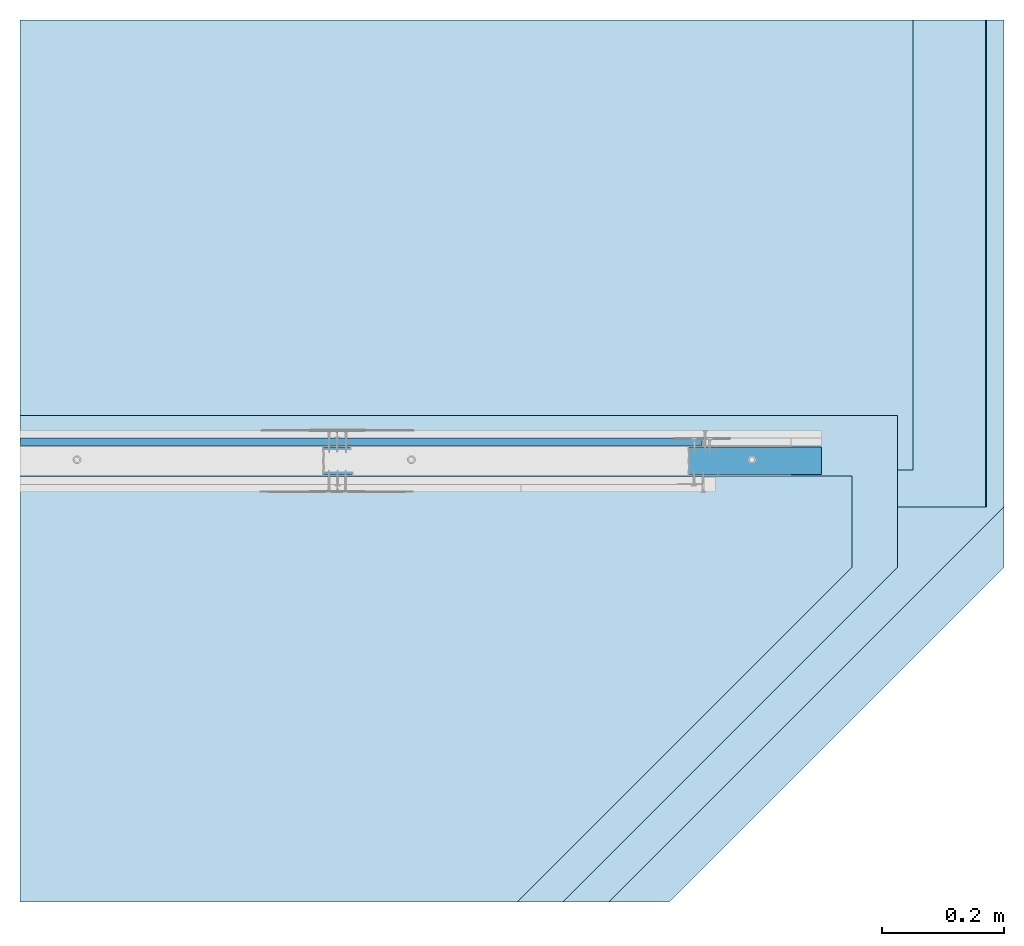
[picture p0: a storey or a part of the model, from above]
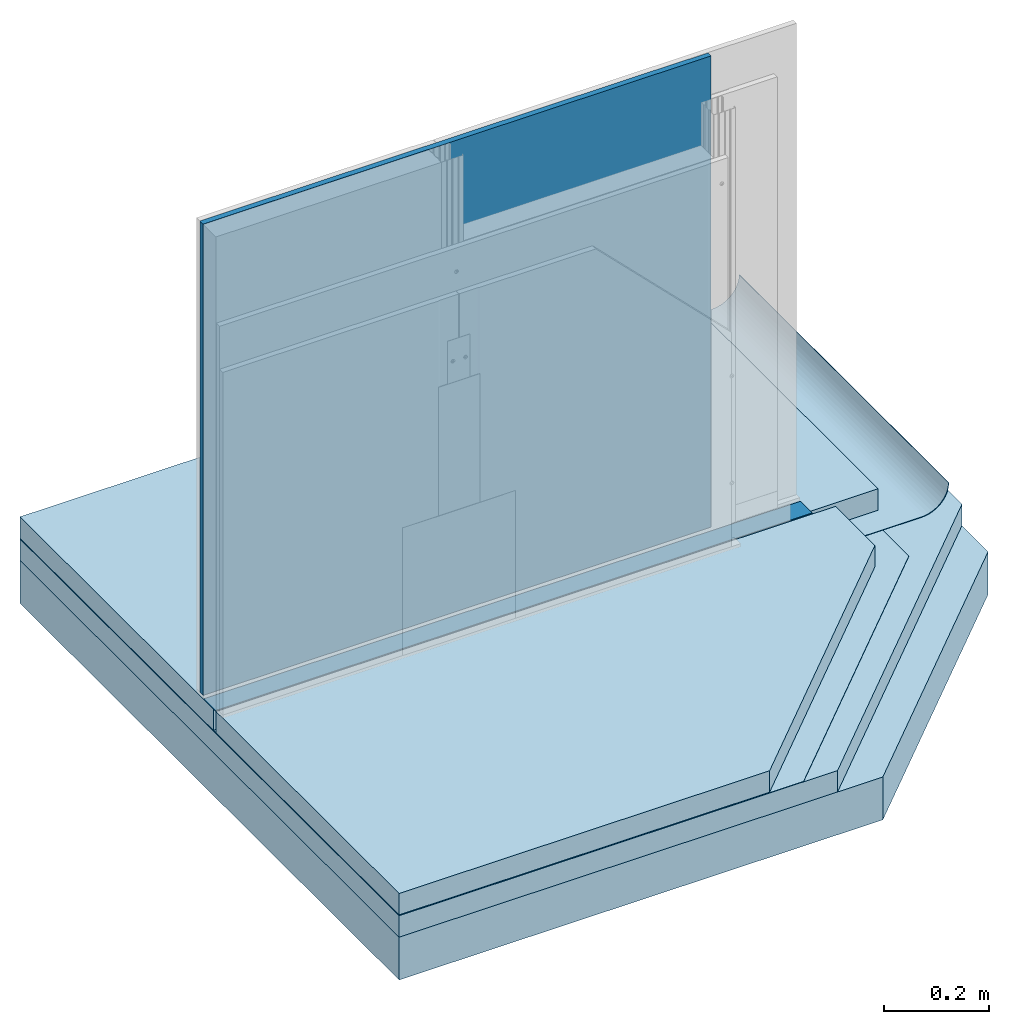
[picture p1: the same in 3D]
Properties of the parts of a building model (IFC2X3)

# File
Description: ViewDefinition [CoordinationView]
Time: 2022-01-05T16:45:41
Made in: SketchUp Pro 2015

# IfcProject, Default Project
Description: Description of Default Project

# IfcSite, Default Site
Description: Description of Default Site; RefLatitude: 24, 28, 0; RefLongitude: 54, 25, 0; RefElevation: 10 mm

# IfcBuilding, Default Building
Description: Description of Default Building

# IfcBuildingStorey, Default Building Storey
In: Default Building
Description: Description of Default Building Storey; Elevation: 0 mm

# IfcSlab (6)
In: Default Building Storey
Description: Description of Object
PredefinedType - IfcSlabTypeEnum: floor
Name
STROP
2 x Wylewka betonowa WEBER
Wełna mineralna szklana lub skalna ISOVER
2 x Folia budowlana PE ISOVER Stopair®

# IfcWall (58)
In: Default Building Storey
Description: Description of Object
Name
20 x Wkręt RIGIPS TN 35
6 x Kołek rozporowy min. fi 6
2 x Profil RIGIPS CW50 ULTRASTIL®
Taśma uszczelniająca piankowa RIGIPS
7 x Płyta gipsowo-kartonowa RIGIPS PRO (4PRO™)
10 x Wkręt RIGIPS TN 25
2 x Dedykowana masa szpachlowa Rigips - wykończeniowa
5 x Dedykowana masa szpachlowa Rigips - konstrukcyjna
2 x Taśma spoinowa RIGIPS
2 x Wełna mineralna szklana lub skalna ISOVER
Profil RIGIPS UW50 ULTRASTIL®
